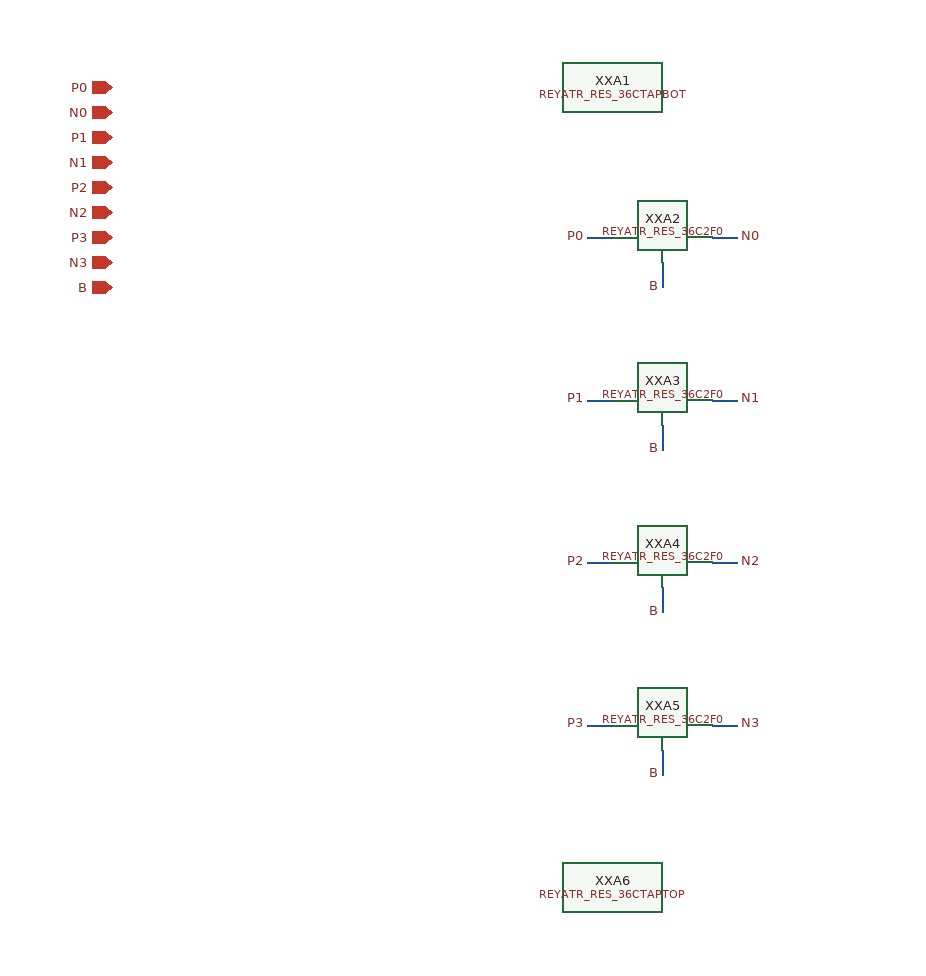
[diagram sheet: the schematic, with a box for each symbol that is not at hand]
v {xschem version=3.0.0 file_version=1.2 }
G {}
K {}
V {}
S {}
E {}
C {devices/iopin.sym} 0 0 0 0 {name=p0 lab=P0}
C {devices/iopin.sym} 0 20 0 0 {name=p1 lab=N0}
C {devices/iopin.sym} 0 40 0 0 {name=p2 lab=P1}
C {devices/iopin.sym} 0 60 0 0 {name=p3 lab=N1}
C {devices/iopin.sym} 0 80 0 0 {name=p4 lab=P2}
C {devices/iopin.sym} 0 100 0 0 {name=p5 lab=N2}
C {devices/iopin.sym} 0 120 0 0 {name=p6 lab=P3}
C {devices/iopin.sym} 0 140 0 0 {name=p7 lab=N3}
C {devices/iopin.sym} 0 160 0 0 {name=p8 lab=B}
C {LELO_TEMP_SKY130A/REYATR_RES_36CTAPBOT.sym} 400 0 0 0 {name=XXA1}
C {LELO_TEMP_SKY130A/REYATR_RES_36C2F0.sym} 400 120.0 0 0 {name=XXA2}
N 500.0 120.0 480.0 120.0 {lab=N0}
C {devices/lab_pin.sym} 500.0 120.0 2 0 {name=l0 sig_type=std_logic lab=N0 }
N 380.0 120.0 400.0 120.0 {lab=P0}
C {devices/lab_pin.sym} 380.0 120.0 0 0 {name=l1 sig_type=std_logic lab=P0 }
N 440.0 160.0 440.0 140.0 {lab=B}
C {devices/lab_pin.sym} 440.0 160.0 1 0 {name=l2 sig_type=std_logic lab=B }
C {LELO_TEMP_SKY130A/REYATR_RES_36C2F0.sym} 400 250.0 0 0 {name=XXA3}
N 500.0 250.0 480.0 250.0 {lab=N1}
C {devices/lab_pin.sym} 500.0 250.0 2 0 {name=l3 sig_type=std_logic lab=N1 }
N 380.0 250.0 400.0 250.0 {lab=P1}
C {devices/lab_pin.sym} 380.0 250.0 0 0 {name=l4 sig_type=std_logic lab=P1 }
N 440.0 290.0 440.0 270.0 {lab=B}
C {devices/lab_pin.sym} 440.0 290.0 1 0 {name=l5 sig_type=std_logic lab=B }
C {LELO_TEMP_SKY130A/REYATR_RES_36C2F0.sym} 400 380.0 0 0 {name=XXA4}
N 500.0 380.0 480.0 380.0 {lab=N2}
C {devices/lab_pin.sym} 500.0 380.0 2 0 {name=l6 sig_type=std_logic lab=N2 }
N 380.0 380.0 400.0 380.0 {lab=P2}
C {devices/lab_pin.sym} 380.0 380.0 0 0 {name=l7 sig_type=std_logic lab=P2 }
N 440.0 420.0 440.0 400.0 {lab=B}
C {devices/lab_pin.sym} 440.0 420.0 1 0 {name=l8 sig_type=std_logic lab=B }
C {LELO_TEMP_SKY130A/REYATR_RES_36C2F0.sym} 400 510.0 0 0 {name=XXA5}
N 500.0 510.0 480.0 510.0 {lab=N3}
C {devices/lab_pin.sym} 500.0 510.0 2 0 {name=l9 sig_type=std_logic lab=N3 }
N 380.0 510.0 400.0 510.0 {lab=P3}
C {devices/lab_pin.sym} 380.0 510.0 0 0 {name=l10 sig_type=std_logic lab=P3 }
N 440.0 550.0 440.0 530.0 {lab=B}
C {devices/lab_pin.sym} 440.0 550.0 1 0 {name=l11 sig_type=std_logic lab=B }
C {LELO_TEMP_SKY130A/REYATR_RES_36CTAPTOP.sym} 400 640.0 0 0 {name=XXA6}
